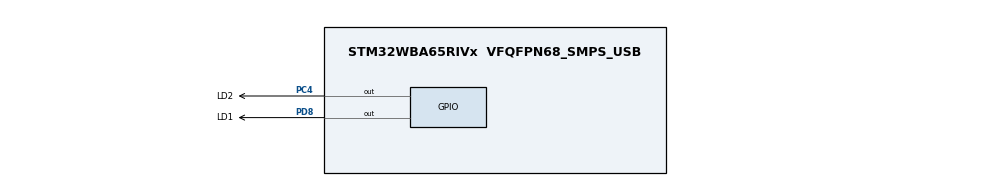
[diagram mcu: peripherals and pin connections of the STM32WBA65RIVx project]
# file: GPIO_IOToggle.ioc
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CORTEX_M33_NS.userName=CORTEX_M33
Mcu.Family=STM32WBA
Mcu.Name=STM32WBA65RIVx
Mcu.Package=VFQFPN68_SMPS_USB
NVIC.PriorityGroup=NVIC_PRIORITYGROUP_4
OSC_IN.Mode=HSE-External-Oscillator
OSC_IN.Signal=RCC_OSC_IN
OSC_OUT.Mode=HSE-External-Oscillator
OSC_OUT.Signal=RCC_OSC_OUT
PC4.GPIO_Label=LD2
PC4.GPIO_Speed=GPIO_SPEED_FREQ_HIGH
PC4.Signal=GPIO_Output
PD8.GPIO_Label=LD1
PD8.GPIO_Speed=GPIO_SPEED_FREQ_HIGH
PD8.Signal=GPIO_Output
ProjectManager.HeapSize=0x200
ProjectManager.StackSize=0x400
ProjectManager.TargetToolchain=EWARM V9.20
RCC.ADCFreq_Value=100000000
RCC.AHB5CLKDivider=DIV4
RCC.AHBFreq_Value=100000000
RCC.APB1Freq_Value=100000000
RCC.APB1TimFreq_Value=100000000
RCC.APB2Freq_Value=100000000
RCC.APB2TimFreq_Value=100000000
RCC.CortexFreq_Value=12500000
RCC.HCLKFreq_Value=100000000
RCC.HSE_VALUE=32000000
RCC.HSI_VALUE=16000000
RCC.LSE_VALUE=32768
RCC.LSI1_VALUE=32000
RCC.LSI2_VALUE=32000
RCC.PLLFRACN=4096
RCC.PLLM=2
RCC.PLLN=12
RCC.PLLSourceVirtual=RCC_PLLSOURCE_HSE
RCC.SYSCLKFreq_VALUE=100000000
RCC.SYSCLKSourceVirtual=RCC_SYSCLKSOURCE_PLLCLK
RCC.VCOOutputFreq_Value=200000000
VP_CORTEX_M33_NS_VS_Hclk.Mode=Hclk_Mode
VP_ICACHE_VS_ICACHE.Mode=DirectMappedCache
VP_PWR_VS_SECSignals.Mode=Security/Privilege
board=custom

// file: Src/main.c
/* USER CODE BEGIN Header */
/**
  ******************************************************************************
  * @file    GPIO/GPIO_IOToggle/Src/main.c
  * @author  MCD Application Team
  * @brief   This example describes how to configure and use GPIOs through
  *          the STM32WBAxx HAL API.
  ******************************************************************************
  * @attention
  *
  * Copyright (c) 2024 STMicroelectronics.
  * All rights reserved.
  *
  * This software is licensed under terms that can be found in the LICENSE file
  * in the root directory of this software component.
  * If no LICENSE file comes with this software, it is provided AS-IS.
  *
  ******************************************************************************
  */
/* USER CODE END Header */
#include "main.h"

void SystemClock_Config(void);
static void MX_GPIO_Init(void);
static void MX_ICACHE_Init(void);

int main(void)
{

  /* USER CODE BEGIN 1 */
  /* STM32WBAxx HAL library initialization:
       - Systick timer is configured by default as source of time base, but user
             can eventually implement his proper time base source (a general purpose
             timer for example or other time source), keeping in mind that Time base
             duration should be kept 1ms since PPP_TIMEOUT_VALUEs are defined and
             handled in milliseconds basis.
       - Set NVIC Group Priority to 4
       - Low Level Initialization
     */
  /* USER CODE END 1 */

  /* MCU Configuration--------------------------------------------------------*/

  /* Reset of all peripherals, Initializes the Flash interface and the Systick. */
  HAL_Init();

  /* Configure the system clock */
  SystemClock_Config();

  /* Initialize all configured peripherals */
  MX_GPIO_Init();
  MX_ICACHE_Init();

  /* Infinite loop */
  while (1)
  {

    /* USER CODE BEGIN 3 */
    HAL_GPIO_TogglePin(LD1_GPIO_PORT, LD1_PIN);
    /* Insert delay 100 ms */
    HAL_Delay(100);
    HAL_GPIO_TogglePin(LD2_GPIO_PORT, LD2_PIN);
    /* Insert delay 100 ms */
    HAL_Delay(100);

  }
  /* USER CODE END 3 */
}

void SystemClock_Config(void)
{
  RCC_OscInitTypeDef RCC_OscInitStruct = {0};
  RCC_ClkInitTypeDef RCC_ClkInitStruct = {0};

  /** Supply configuration update enable
  */
  HAL_PWREx_ConfigSupply(PWR_LDO_SUPPLY);

  /** Configure the main internal regulator output voltage
  */
  if (HAL_PWREx_ControlVoltageScaling(PWR_REGULATOR_VOLTAGE_SCALE1) != HAL_OK)
  {
    Error_Handler();
  }

  /** Initializes the CPU, AHB and APB busses clocks
  */
  RCC_OscInitStruct.OscillatorType = RCC_OSCILLATORTYPE_HSE;
  RCC_OscInitStruct.HSEState = RCC_HSE_ON;
  RCC_OscInitStruct.HSEDiv = RCC_HSE_DIV1;
  RCC_OscInitStruct.PLL1.PLLState = RCC_PLL_ON;
  RCC_OscInitStruct.PLL1.PLLSource = RCC_PLLSOURCE_HSE;
  RCC_OscInitStruct.PLL1.PLLM = 2;
  RCC_OscInitStruct.PLL1.PLLN = 12;
  RCC_OscInitStruct.PLL1.PLLP = 2;
  RCC_OscInitStruct.PLL1.PLLQ = 2;
  RCC_OscInitStruct.PLL1.PLLR = 2;
  RCC_OscInitStruct.PLL1.PLLFractional = 4096;
  if (HAL_RCC_OscConfig(&RCC_OscInitStruct) != HAL_OK)
  {
    Error_Handler();
  }

  /** Initializes the CPU, AHB and APB busses clocks
  */
  RCC_ClkInitStruct.ClockType = RCC_CLOCKTYPE_HCLK|RCC_CLOCKTYPE_SYSCLK
                              |RCC_CLOCKTYPE_PCLK1|RCC_CLOCKTYPE_PCLK2
                              |RCC_CLOCKTYPE_PCLK7|RCC_CLOCKTYPE_HCLK5;
  RCC_ClkInitStruct.SYSCLKSource = RCC_SYSCLKSOURCE_PLLCLK;
  RCC_ClkInitStruct.AHBCLKDivider = RCC_SYSCLK_DIV1;
  RCC_ClkInitStruct.APB1CLKDivider = RCC_HCLK_DIV1;
  RCC_ClkInitStruct.APB2CLKDivider = RCC_HCLK_DIV1;
  RCC_ClkInitStruct.APB7CLKDivider = RCC_HCLK_DIV1;
  RCC_ClkInitStruct.AHB5_PLL1_CLKDivider = RCC_SYSCLK_PLL1_DIV4;
  RCC_ClkInitStruct.AHB5_HSEHSI_CLKDivider = RCC_SYSCLK_HSEHSI_DIV1;

  if (HAL_RCC_ClockConfig(&RCC_ClkInitStruct, FLASH_LATENCY_3) != HAL_OK)
  {
    Error_Handler();
  }
}

static void MX_ICACHE_Init(void)
{

  /** Enable instruction cache in 1-way (direct mapped cache)
  */
  if (HAL_ICACHE_ConfigAssociativityMode(ICACHE_1WAY) != HAL_OK)
  {
    Error_Handler();
  }
  if (HAL_ICACHE_Enable() != HAL_OK)
  {
    Error_Handler();
  }

}

static void MX_GPIO_Init(void)
{
  GPIO_InitTypeDef GPIO_InitStruct = {0};

  /* GPIO Ports Clock Enable */
  __HAL_RCC_GPIOD_CLK_ENABLE();
  __HAL_RCC_GPIOC_CLK_ENABLE();

  /*Configure GPIO pin Output Level */
  HAL_GPIO_WritePin(LD1_GPIO_Port, LD1_Pin, GPIO_PIN_RESET);

  /*Configure GPIO pin Output Level */
  HAL_GPIO_WritePin(LD2_GPIO_Port, LD2_Pin, GPIO_PIN_RESET);

  /*Configure GPIO pin : LD1_Pin */
  GPIO_InitStruct.Pin = LD1_Pin;
  GPIO_InitStruct.Mode = GPIO_MODE_OUTPUT_PP;
  GPIO_InitStruct.Pull = GPIO_NOPULL;
  GPIO_InitStruct.Speed = GPIO_SPEED_FREQ_HIGH;
  HAL_GPIO_Init(LD1_GPIO_Port, &GPIO_InitStruct);

  /*Configure GPIO pin : LD2_Pin */
  GPIO_InitStruct.Pin = LD2_Pin;
  GPIO_InitStruct.Mode = GPIO_MODE_OUTPUT_PP;
  GPIO_InitStruct.Pull = GPIO_NOPULL;
  GPIO_InitStruct.Speed = GPIO_SPEED_FREQ_HIGH;
  HAL_GPIO_Init(LD2_GPIO_Port, &GPIO_InitStruct);

}

void Error_Handler(void)
{
  while(1)
  {
  }
}
